VERSION 5.7 ;
  NOWIREEXTENSIONATPIN ON ;
  DIVIDERCHAR "/" ;
  BUSBITCHARS "[]" ;
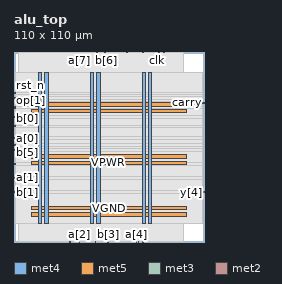
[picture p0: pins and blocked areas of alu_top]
MACRO alu_top
  CLASS BLOCK ;
  FOREIGN alu_top ;
  ORIGIN 0.000 0.000 ;
  SIZE 110.000 BY 110.000 ;
  PIN VGND
    DIRECTION INOUT ;
    USE GROUND ;
    PORT
      LAYER met4 ;
        RECT 17.820 10.640 19.820 98.160 ;
    END
    PORT
      LAYER met4 ;
        RECT 47.820 10.640 49.820 98.160 ;
    END
    PORT
      LAYER met4 ;
        RECT 77.820 10.640 79.820 98.160 ;
    END
    PORT
      LAYER met5 ;
        RECT 10.120 18.580 99.820 20.580 ;
    END
    PORT
      LAYER met5 ;
        RECT 10.120 48.580 99.820 50.580 ;
    END
    PORT
      LAYER met5 ;
        RECT 10.120 78.580 99.820 80.580 ;
    END
  END VGND
  PIN VPWR
    DIRECTION INOUT ;
    USE POWER ;
    PORT
      LAYER met4 ;
        RECT 14.120 10.640 16.120 98.160 ;
    END
    PORT
      LAYER met4 ;
        RECT 44.120 10.640 46.120 98.160 ;
    END
    PORT
      LAYER met4 ;
        RECT 74.120 10.640 76.120 98.160 ;
    END
    PORT
      LAYER met5 ;
        RECT 10.120 14.880 99.820 16.880 ;
    END
    PORT
      LAYER met5 ;
        RECT 10.120 44.880 99.820 46.880 ;
    END
    PORT
      LAYER met5 ;
        RECT 10.120 74.880 99.820 76.880 ;
    END
  END VPWR
  PIN a[0]
    DIRECTION INPUT ;
    USE SIGNAL ;
    ANTENNAGATEAREA 0.213000 ;
    PORT
      LAYER met3 ;
        RECT 0.000 59.880 0.600 60.480 ;
    END
  END a[0]
  PIN a[1]
    DIRECTION INPUT ;
    USE SIGNAL ;
    ANTENNAGATEAREA 0.213000 ;
    PORT
      LAYER met3 ;
        RECT 0.000 36.760 0.600 37.360 ;
    END
  END a[1]
  PIN a[2]
    DIRECTION INPUT ;
    USE SIGNAL ;
    ANTENNAGATEAREA 0.213000 ;
    PORT
      LAYER met2 ;
        RECT 37.810 0.000 38.090 0.280 ;
    END
  END a[2]
  PIN a[3]
    DIRECTION INPUT ;
    USE SIGNAL ;
    ANTENNAGATEAREA 0.213000 ;
    PORT
      LAYER met2 ;
        RECT 47.010 0.000 47.290 0.280 ;
    END
  END a[3]
  PIN a[4]
    DIRECTION INPUT ;
    USE SIGNAL ;
    ANTENNAGATEAREA 0.213000 ;
    PORT
      LAYER met2 ;
        RECT 70.930 0.000 71.210 0.280 ;
    END
  END a[4]
  PIN a[5]
    DIRECTION INPUT ;
    USE SIGNAL ;
    ANTENNAGATEAREA 0.213000 ;
    PORT
      LAYER met2 ;
        RECT 52.530 109.720 52.810 110.000 ;
    END
  END a[5]
  PIN a[6]
    DIRECTION INPUT ;
    USE SIGNAL ;
    ANTENNAGATEAREA 0.213000 ;
    PORT
      LAYER met2 ;
        RECT 47.930 109.720 48.210 110.000 ;
    END
  END a[6]
  PIN a[7]
    DIRECTION INPUT ;
    USE SIGNAL ;
    ANTENNAGATEAREA 0.213000 ;
    PORT
      LAYER met2 ;
        RECT 37.810 109.720 38.090 110.000 ;
    END
  END a[7]
  PIN b[0]
    DIRECTION INPUT ;
    USE SIGNAL ;
    ANTENNAGATEAREA 0.213000 ;
    PORT
      LAYER met3 ;
        RECT 0.000 66.680 0.600 67.280 ;
    END
  END b[0]
  PIN b[1]
    DIRECTION INPUT ;
    USE SIGNAL ;
    ANTENNAGATEAREA 0.213000 ;
    PORT
      LAYER met3 ;
        RECT 0.000 28.600 0.600 29.200 ;
    END
  END b[1]
  PIN b[2]
    DIRECTION INPUT ;
    USE SIGNAL ;
    ANTENNAGATEAREA 0.213000 ;
    PORT
      LAYER met2 ;
        RECT 32.290 0.000 32.570 0.280 ;
    END
  END b[2]
  PIN b[3]
    DIRECTION INPUT ;
    USE SIGNAL ;
    ANTENNAGATEAREA 0.213000 ;
    PORT
      LAYER met2 ;
        RECT 54.370 0.000 54.650 0.280 ;
    END
  END b[3]
  PIN b[4]
    DIRECTION INPUT ;
    USE SIGNAL ;
    ANTENNAGATEAREA 0.213000 ;
    PORT
      LAYER met2 ;
        RECT 74.610 0.000 74.890 0.280 ;
    END
  END b[4]
  PIN b[5]
    DIRECTION INPUT ;
    USE SIGNAL ;
    ANTENNAGATEAREA 0.213000 ;
    PORT
      LAYER met3 ;
        RECT 0.000 55.800 0.600 56.400 ;
    END
  END b[5]
  PIN b[6]
    DIRECTION INPUT ;
    USE SIGNAL ;
    ANTENNAGATEAREA 0.213000 ;
    PORT
      LAYER met2 ;
        RECT 53.450 109.720 53.730 110.000 ;
    END
  END b[6]
  PIN b[7]
    DIRECTION INPUT ;
    USE SIGNAL ;
    ANTENNAGATEAREA 0.213000 ;
    PORT
      LAYER met2 ;
        RECT 35.970 109.720 36.250 110.000 ;
    END
  END b[7]
  PIN carry
    DIRECTION OUTPUT ;
    USE SIGNAL ;
    ANTENNADIFFAREA 0.702900 ;
    PORT
      LAYER met3 ;
        RECT 109.400 80.280 110.000 80.880 ;
    END
  END carry
  PIN clk
    DIRECTION INPUT ;
    USE SIGNAL ;
    ANTENNAGATEAREA 0.852000 ;
    PORT
      LAYER met2 ;
        RECT 82.890 109.720 83.170 110.000 ;
    END
  END clk
  PIN negative
    DIRECTION OUTPUT ;
    USE SIGNAL ;
    ANTENNADIFFAREA 0.702900 ;
    PORT
      LAYER met2 ;
        RECT 73.690 109.720 73.970 110.000 ;
    END
  END negative
  PIN op[0]
    DIRECTION INPUT ;
    USE SIGNAL ;
    ANTENNAGATEAREA 0.213000 ;
    PORT
      LAYER met3 ;
        RECT 0.000 72.120 0.600 72.720 ;
    END
  END op[0]
  PIN op[1]
    DIRECTION INPUT ;
    USE SIGNAL ;
    ANTENNAGATEAREA 0.213000 ;
    PORT
      LAYER met3 ;
        RECT 0.000 77.560 0.600 78.160 ;
    END
  END op[1]
  PIN op[2]
    DIRECTION INPUT ;
    USE SIGNAL ;
    ANTENNAGATEAREA 0.213000 ;
    PORT
      LAYER met3 ;
        RECT 0.000 83.000 0.600 83.600 ;
    END
  END op[2]
  PIN overflow
    DIRECTION OUTPUT ;
    USE SIGNAL ;
    ANTENNADIFFAREA 0.702900 ;
    PORT
      LAYER met2 ;
        RECT 86.570 109.720 86.850 110.000 ;
    END
  END overflow
  PIN rst_n
    DIRECTION INPUT ;
    USE SIGNAL ;
    ANTENNAGATEAREA 0.213000 ;
    PORT
      LAYER met3 ;
        RECT 0.000 85.720 0.600 86.320 ;
    END
  END rst_n
  PIN y[0]
    DIRECTION OUTPUT ;
    USE SIGNAL ;
    ANTENNADIFFAREA 0.702900 ;
    PORT
      LAYER met3 ;
        RECT 0.000 53.080 0.600 53.680 ;
    END
  END y[0]
  PIN y[1]
    DIRECTION OUTPUT ;
    USE SIGNAL ;
    ANTENNADIFFAREA 0.702900 ;
    PORT
      LAYER met3 ;
        RECT 0.000 44.920 0.600 45.520 ;
    END
  END y[1]
  PIN y[2]
    DIRECTION OUTPUT ;
    USE SIGNAL ;
    ANTENNADIFFAREA 0.702900 ;
    PORT
      LAYER met2 ;
        RECT 58.050 109.720 58.330 110.000 ;
    END
  END y[2]
  PIN y[3]
    DIRECTION OUTPUT ;
    USE SIGNAL ;
    ANTENNADIFFAREA 0.702900 ;
    PORT
      LAYER met2 ;
        RECT 71.850 0.000 72.130 0.280 ;
    END
  END y[3]
  PIN y[4]
    DIRECTION OUTPUT ;
    USE SIGNAL ;
    ANTENNADIFFAREA 0.702900 ;
    PORT
      LAYER met3 ;
        RECT 109.400 28.600 110.000 29.200 ;
    END
  END y[4]
  PIN y[5]
    DIRECTION OUTPUT ;
    USE SIGNAL ;
    ANTENNADIFFAREA 0.702900 ;
    PORT
      LAYER met2 ;
        RECT 65.410 109.720 65.690 110.000 ;
    END
  END y[5]
  PIN y[6]
    DIRECTION OUTPUT ;
    USE SIGNAL ;
    ANTENNADIFFAREA 0.702900 ;
    PORT
      LAYER met2 ;
        RECT 83.810 109.720 84.090 110.000 ;
    END
  END y[6]
  PIN y[7]
    DIRECTION OUTPUT ;
    USE SIGNAL ;
    ANTENNADIFFAREA 0.702900 ;
    PORT
      LAYER met2 ;
        RECT 74.610 109.720 74.890 110.000 ;
    END
  END y[7]
  PIN zero
    DIRECTION OUTPUT ;
    USE SIGNAL ;
    ANTENNADIFFAREA 0.702900 ;
    PORT
      LAYER met2 ;
        RECT 67.250 109.720 67.530 110.000 ;
    END
  END zero
  OBS
      LAYER nwell ;
        RECT 9.930 10.795 100.010 98.005 ;
      LAYER li1 ;
        RECT 10.120 10.795 99.820 98.005 ;
      LAYER met1 ;
        RECT 2.830 10.640 99.820 98.160 ;
      LAYER met2 ;
        RECT 2.850 109.440 35.690 109.720 ;
        RECT 36.530 109.440 37.530 109.720 ;
        RECT 38.370 109.440 47.650 109.720 ;
        RECT 48.490 109.440 52.250 109.720 ;
        RECT 53.090 109.440 53.170 109.720 ;
        RECT 54.010 109.440 57.770 109.720 ;
        RECT 58.610 109.440 65.130 109.720 ;
        RECT 65.970 109.440 66.970 109.720 ;
        RECT 67.810 109.440 73.410 109.720 ;
        RECT 74.250 109.440 74.330 109.720 ;
        RECT 75.170 109.440 82.610 109.720 ;
        RECT 83.450 109.440 83.530 109.720 ;
        RECT 84.370 109.440 86.290 109.720 ;
        RECT 87.130 109.440 98.350 109.720 ;
        RECT 2.850 0.560 98.350 109.440 ;
        RECT 2.850 0.280 32.010 0.560 ;
        RECT 32.850 0.280 37.530 0.560 ;
        RECT 38.370 0.280 46.730 0.560 ;
        RECT 47.570 0.280 54.090 0.560 ;
        RECT 54.930 0.280 70.650 0.560 ;
        RECT 71.490 0.280 71.570 0.560 ;
        RECT 72.410 0.280 74.330 0.560 ;
        RECT 75.170 0.280 98.350 0.560 ;
      LAYER met3 ;
        RECT 0.600 86.720 109.400 98.085 ;
        RECT 1.000 85.320 109.400 86.720 ;
        RECT 0.600 84.000 109.400 85.320 ;
        RECT 1.000 82.600 109.400 84.000 ;
        RECT 0.600 81.280 109.400 82.600 ;
        RECT 0.600 79.880 109.000 81.280 ;
        RECT 0.600 78.560 109.400 79.880 ;
        RECT 1.000 77.160 109.400 78.560 ;
        RECT 0.600 73.120 109.400 77.160 ;
        RECT 1.000 71.720 109.400 73.120 ;
        RECT 0.600 67.680 109.400 71.720 ;
        RECT 1.000 66.280 109.400 67.680 ;
        RECT 0.600 60.880 109.400 66.280 ;
        RECT 1.000 59.480 109.400 60.880 ;
        RECT 0.600 56.800 109.400 59.480 ;
        RECT 1.000 55.400 109.400 56.800 ;
        RECT 0.600 54.080 109.400 55.400 ;
        RECT 1.000 52.680 109.400 54.080 ;
        RECT 0.600 45.920 109.400 52.680 ;
        RECT 1.000 44.520 109.400 45.920 ;
        RECT 0.600 37.760 109.400 44.520 ;
        RECT 1.000 36.360 109.400 37.760 ;
        RECT 0.600 29.600 109.400 36.360 ;
        RECT 1.000 28.200 109.000 29.600 ;
        RECT 0.600 10.715 109.400 28.200 ;
  END
END alu_top
END LIBRARY

